VERSION 5.7 ;
  NOWIREEXTENSIONATPIN ON ;
  DIVIDERCHAR "/" ;
  BUSBITCHARS "[]" ;
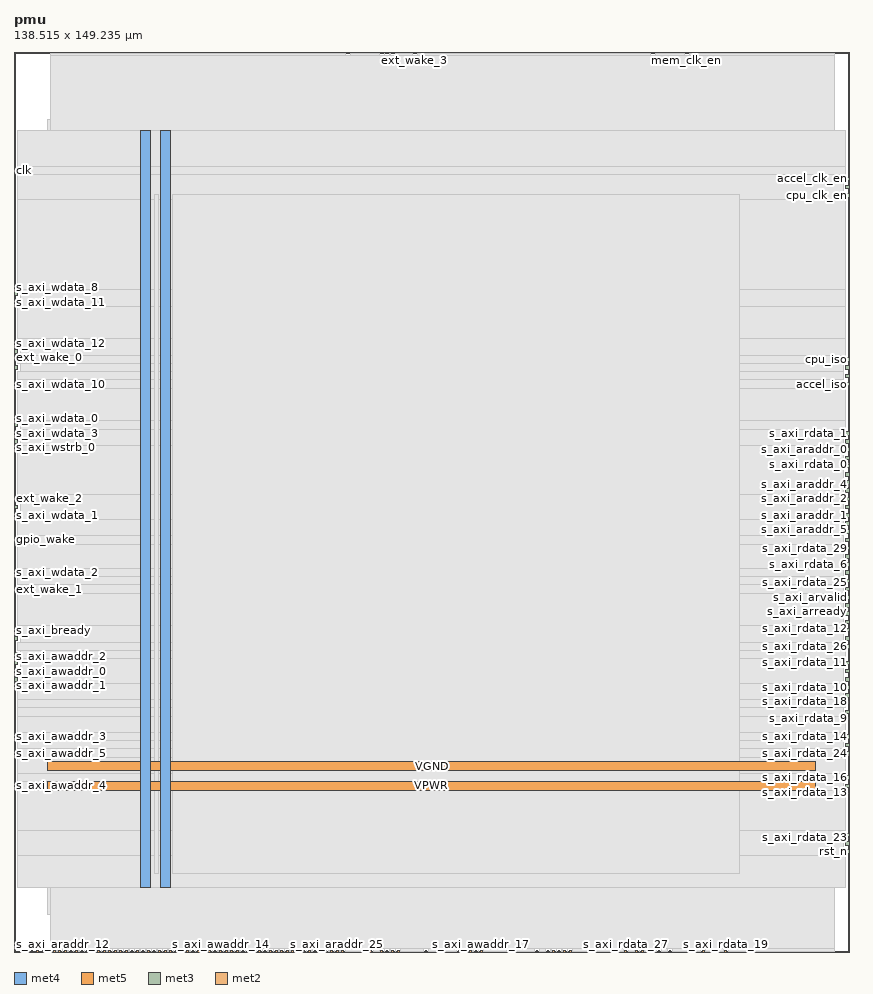
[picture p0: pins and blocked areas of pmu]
MACRO pmu
  CLASS BLOCK ;
  FOREIGN pmu ;
  ORIGIN 0.000 0.000 ;
  SIZE 138.515 BY 149.235 ;
  PIN VGND
    DIRECTION INOUT ;
    USE GROUND ;
    PORT
      LAYER met4 ;
        RECT 24.340 10.640 25.940 136.240 ;
    END
    PORT
      LAYER met5 ;
        RECT 5.520 30.030 132.940 31.630 ;
    END
  END VGND
  PIN VPWR
    DIRECTION INOUT ;
    USE POWER ;
    PORT
      LAYER met4 ;
        RECT 21.040 10.640 22.640 136.240 ;
    END
    PORT
      LAYER met5 ;
        RECT 5.520 26.730 132.940 28.330 ;
    END
  END VPWR
  PIN accel_clk_en
    DIRECTION OUTPUT ;
    USE SIGNAL ;
    ANTENNAGATEAREA 0.434700 ;
    ANTENNADIFFAREA 1.137600 ;
    PORT
      LAYER met3 ;
        RECT 137.915 127.880 138.515 128.480 ;
    END
  END accel_clk_en
  PIN accel_iso
    DIRECTION OUTPUT ;
    USE SIGNAL ;
    ANTENNAGATEAREA 0.434700 ;
    ANTENNADIFFAREA 1.137600 ;
    PORT
      LAYER met3 ;
        RECT 137.915 93.880 138.515 94.480 ;
    END
  END accel_iso
  PIN clk
    DIRECTION INPUT ;
    USE SIGNAL ;
    ANTENNAGATEAREA 1.286700 ;
    ANTENNADIFFAREA 0.434700 ;
    PORT
      LAYER met3 ;
        RECT 0.000 129.240 0.600 129.840 ;
    END
  END clk
  PIN cpu_clk_en
    DIRECTION OUTPUT ;
    USE SIGNAL ;
    ANTENNAGATEAREA 0.434700 ;
    ANTENNADIFFAREA 1.137600 ;
    PORT
      LAYER met3 ;
        RECT 137.915 125.160 138.515 125.760 ;
    END
  END cpu_clk_en
  PIN cpu_iso
    DIRECTION OUTPUT ;
    USE SIGNAL ;
    ANTENNAGATEAREA 0.434700 ;
    ANTENNADIFFAREA 1.137600 ;
    PORT
      LAYER met3 ;
        RECT 137.915 97.960 138.515 98.560 ;
    END
  END cpu_iso
  PIN ext_wake_0
    DIRECTION INPUT ;
    USE SIGNAL ;
    ANTENNAGATEAREA 0.647700 ;
    ANTENNADIFFAREA 0.434700 ;
    PORT
      LAYER met3 ;
        RECT 0.000 99.320 0.600 99.920 ;
    END
  END ext_wake_0
  PIN ext_wake_1
    DIRECTION INPUT ;
    USE SIGNAL ;
    ANTENNAGATEAREA 0.647700 ;
    ANTENNADIFFAREA 0.434700 ;
    PORT
      LAYER met3 ;
        RECT 0.000 59.880 0.600 60.480 ;
    END
  END ext_wake_1
  PIN ext_wake_2
    DIRECTION INPUT ;
    USE SIGNAL ;
    ANTENNAGATEAREA 0.647700 ;
    ANTENNADIFFAREA 0.434700 ;
    PORT
      LAYER met3 ;
        RECT 0.000 74.840 0.600 75.440 ;
    END
  END ext_wake_2
  PIN ext_wake_3
    DIRECTION INPUT ;
    USE SIGNAL ;
    ANTENNAGATEAREA 0.647700 ;
    ANTENNADIFFAREA 0.434700 ;
    PORT
      LAYER met2 ;
        RECT 66.330 148.955 66.610 149.235 ;
    END
  END ext_wake_3
  PIN gpio_wake
    DIRECTION INPUT ;
    USE SIGNAL ;
    ANTENNAGATEAREA 0.647700 ;
    ANTENNADIFFAREA 0.434700 ;
    PORT
      LAYER met3 ;
        RECT 0.000 68.040 0.600 68.640 ;
    END
  END gpio_wake
  PIN mem_clk_en
    DIRECTION OUTPUT ;
    USE SIGNAL ;
    ANTENNAGATEAREA 0.434700 ;
    ANTENNADIFFAREA 1.137600 ;
    PORT
      LAYER met2 ;
        RECT 111.410 148.955 111.690 149.235 ;
    END
  END mem_clk_en
  PIN periph_clk_en
    DIRECTION OUTPUT ;
    USE SIGNAL ;
    ANTENNAGATEAREA 0.434700 ;
    ANTENNADIFFAREA 1.137600 ;
    PORT
      LAYER met3 ;
        RECT 137.915 126.520 138.515 127.120 ;
    END
  END periph_clk_en
  PIN periph_iso
    DIRECTION OUTPUT ;
    USE SIGNAL ;
    ANTENNAGATEAREA 0.434700 ;
    ANTENNADIFFAREA 1.137600 ;
    PORT
      LAYER met3 ;
        RECT 137.915 96.600 138.515 97.200 ;
    END
  END periph_iso
  PIN rst_n
    DIRECTION INPUT ;
    USE SIGNAL ;
    ANTENNAGATEAREA 0.647700 ;
    ANTENNADIFFAREA 0.434700 ;
    PORT
      LAYER met3 ;
        RECT 137.915 16.360 138.515 16.960 ;
    END
  END rst_n
  PIN s_axi_araddr_0
    DIRECTION INPUT ;
    USE SIGNAL ;
    ANTENNAGATEAREA 0.647700 ;
    ANTENNADIFFAREA 0.434700 ;
    PORT
      LAYER met3 ;
        RECT 137.915 83.000 138.515 83.600 ;
    END
  END s_axi_araddr_0
  PIN s_axi_araddr_1
    DIRECTION INPUT ;
    USE SIGNAL ;
    ANTENNAGATEAREA 0.647700 ;
    ANTENNADIFFAREA 0.434700 ;
    PORT
      LAYER met3 ;
        RECT 137.915 72.120 138.515 72.720 ;
    END
  END s_axi_araddr_1
  PIN s_axi_araddr_10
    DIRECTION INPUT ;
    USE SIGNAL ;
    PORT
      LAYER met2 ;
        RECT 3.770 0.000 4.050 0.280 ;
    END
  END s_axi_araddr_10
  PIN s_axi_araddr_11
    DIRECTION INPUT ;
    USE SIGNAL ;
    PORT
      LAYER met2 ;
        RECT 2.850 0.000 3.130 0.280 ;
    END
  END s_axi_araddr_11
  PIN s_axi_araddr_12
    DIRECTION INPUT ;
    USE SIGNAL ;
    PORT
      LAYER met2 ;
        RECT 5.610 0.000 5.890 0.280 ;
    END
  END s_axi_araddr_12
  PIN s_axi_araddr_13
    DIRECTION INPUT ;
    USE SIGNAL ;
    PORT
      LAYER met2 ;
        RECT 4.690 0.000 4.970 0.280 ;
    END
  END s_axi_araddr_13
  PIN s_axi_araddr_14
    DIRECTION INPUT ;
    USE SIGNAL ;
    PORT
      LAYER met2 ;
        RECT 7.450 0.000 7.730 0.280 ;
    END
  END s_axi_araddr_14
  PIN s_axi_araddr_15
    DIRECTION INPUT ;
    USE SIGNAL ;
    PORT
      LAYER met2 ;
        RECT 6.530 0.000 6.810 0.280 ;
    END
  END s_axi_araddr_15
  PIN s_axi_araddr_16
    DIRECTION INPUT ;
    USE SIGNAL ;
    PORT
      LAYER met2 ;
        RECT 9.290 0.000 9.570 0.280 ;
    END
  END s_axi_araddr_16
  PIN s_axi_araddr_17
    DIRECTION INPUT ;
    USE SIGNAL ;
    PORT
      LAYER met2 ;
        RECT 8.370 0.000 8.650 0.280 ;
    END
  END s_axi_araddr_17
  PIN s_axi_araddr_18
    DIRECTION INPUT ;
    USE SIGNAL ;
    PORT
      LAYER met2 ;
        RECT 52.530 0.000 52.810 0.280 ;
    END
  END s_axi_araddr_18
  PIN s_axi_araddr_19
    DIRECTION INPUT ;
    USE SIGNAL ;
    PORT
      LAYER met2 ;
        RECT 10.210 0.000 10.490 0.280 ;
    END
  END s_axi_araddr_19
  PIN s_axi_araddr_2
    DIRECTION INPUT ;
    USE SIGNAL ;
    ANTENNAGATEAREA 0.647700 ;
    ANTENNADIFFAREA 0.434700 ;
    PORT
      LAYER met3 ;
        RECT 137.915 74.840 138.515 75.440 ;
    END
  END s_axi_araddr_2
  PIN s_axi_araddr_20
    DIRECTION INPUT ;
    USE SIGNAL ;
    PORT
      LAYER met2 ;
        RECT 11.130 0.000 11.410 0.280 ;
    END
  END s_axi_araddr_20
  PIN s_axi_araddr_21
    DIRECTION INPUT ;
    USE SIGNAL ;
    PORT
      LAYER met2 ;
        RECT 12.050 0.000 12.330 0.280 ;
    END
  END s_axi_araddr_21
  PIN s_axi_araddr_22
    DIRECTION INPUT ;
    USE SIGNAL ;
    PORT
      LAYER met2 ;
        RECT 12.970 0.000 13.250 0.280 ;
    END
  END s_axi_araddr_22
  PIN s_axi_araddr_23
    DIRECTION INPUT ;
    USE SIGNAL ;
    PORT
      LAYER met2 ;
        RECT 13.890 0.000 14.170 0.280 ;
    END
  END s_axi_araddr_23
  PIN s_axi_araddr_24
    DIRECTION INPUT ;
    USE SIGNAL ;
    PORT
      LAYER met2 ;
        RECT 14.810 0.000 15.090 0.280 ;
    END
  END s_axi_araddr_24
  PIN s_axi_araddr_25
    DIRECTION INPUT ;
    USE SIGNAL ;
    PORT
      LAYER met2 ;
        RECT 53.450 0.000 53.730 0.280 ;
    END
  END s_axi_araddr_25
  PIN s_axi_araddr_26
    DIRECTION INPUT ;
    USE SIGNAL ;
    PORT
      LAYER met2 ;
        RECT 16.650 0.000 16.930 0.280 ;
    END
  END s_axi_araddr_26
  PIN s_axi_araddr_27
    DIRECTION INPUT ;
    USE SIGNAL ;
    PORT
      LAYER met2 ;
        RECT 17.570 0.000 17.850 0.280 ;
    END
  END s_axi_araddr_27
  PIN s_axi_araddr_28
    DIRECTION INPUT ;
    USE SIGNAL ;
    PORT
      LAYER met2 ;
        RECT 18.490 0.000 18.770 0.280 ;
    END
  END s_axi_araddr_28
  PIN s_axi_araddr_29
    DIRECTION INPUT ;
    USE SIGNAL ;
    PORT
      LAYER met2 ;
        RECT 20.330 0.000 20.610 0.280 ;
    END
  END s_axi_araddr_29
  PIN s_axi_araddr_3
    DIRECTION INPUT ;
    USE SIGNAL ;
    ANTENNAGATEAREA 0.647700 ;
    ANTENNADIFFAREA 0.434700 ;
    PORT
      LAYER met3 ;
        RECT 137.915 73.480 138.515 74.080 ;
    END
  END s_axi_araddr_3
  PIN s_axi_araddr_30
    DIRECTION INPUT ;
    USE SIGNAL ;
    PORT
      LAYER met2 ;
        RECT 21.250 0.000 21.530 0.280 ;
    END
  END s_axi_araddr_30
  PIN s_axi_araddr_31
    DIRECTION INPUT ;
    USE SIGNAL ;
    PORT
      LAYER met2 ;
        RECT 22.170 0.000 22.450 0.280 ;
    END
  END s_axi_araddr_31
  PIN s_axi_araddr_4
    DIRECTION INPUT ;
    USE SIGNAL ;
    ANTENNAGATEAREA 0.647700 ;
    ANTENNADIFFAREA 0.434700 ;
    PORT
      LAYER met3 ;
        RECT 137.915 76.200 138.515 76.800 ;
    END
  END s_axi_araddr_4
  PIN s_axi_araddr_5
    DIRECTION INPUT ;
    USE SIGNAL ;
    ANTENNAGATEAREA 0.647700 ;
    ANTENNADIFFAREA 0.434700 ;
    PORT
      LAYER met3 ;
        RECT 137.915 70.760 138.515 71.360 ;
    END
  END s_axi_araddr_5
  PIN s_axi_araddr_6
    DIRECTION INPUT ;
    USE SIGNAL ;
    ANTENNAGATEAREA 0.647700 ;
    ANTENNADIFFAREA 0.434700 ;
    PORT
      LAYER met3 ;
        RECT 137.915 77.560 138.515 78.160 ;
    END
  END s_axi_araddr_6
  PIN s_axi_araddr_7
    DIRECTION INPUT ;
    USE SIGNAL ;
    ANTENNAGATEAREA 0.647700 ;
    ANTENNADIFFAREA 0.434700 ;
    PORT
      LAYER met3 ;
        RECT 137.915 69.400 138.515 70.000 ;
    END
  END s_axi_araddr_7
  PIN s_axi_araddr_8
    DIRECTION INPUT ;
    USE SIGNAL ;
    PORT
      LAYER met2 ;
        RECT 23.090 0.000 23.370 0.280 ;
    END
  END s_axi_araddr_8
  PIN s_axi_araddr_9
    DIRECTION INPUT ;
    USE SIGNAL ;
    PORT
      LAYER met2 ;
        RECT 54.370 0.000 54.650 0.280 ;
    END
  END s_axi_araddr_9
  PIN s_axi_arready
    DIRECTION OUTPUT ;
    USE SIGNAL ;
    ANTENNAGATEAREA 0.434700 ;
    ANTENNADIFFAREA 1.137600 ;
    PORT
      LAYER met3 ;
        RECT 137.915 57.160 138.515 57.760 ;
    END
  END s_axi_arready
  PIN s_axi_arvalid
    DIRECTION INPUT ;
    USE SIGNAL ;
    ANTENNAGATEAREA 0.647700 ;
    ANTENNADIFFAREA 0.434700 ;
    PORT
      LAYER met3 ;
        RECT 137.915 58.520 138.515 59.120 ;
    END
  END s_axi_arvalid
  PIN s_axi_awaddr_0
    DIRECTION INPUT ;
    USE SIGNAL ;
    ANTENNAGATEAREA 0.647700 ;
    ANTENNADIFFAREA 0.434700 ;
    PORT
      LAYER met3 ;
        RECT 0.000 46.280 0.600 46.880 ;
    END
  END s_axi_awaddr_0
  PIN s_axi_awaddr_1
    DIRECTION INPUT ;
    USE SIGNAL ;
    ANTENNAGATEAREA 0.647700 ;
    ANTENNADIFFAREA 0.434700 ;
    PORT
      LAYER met3 ;
        RECT 0.000 44.920 0.600 45.520 ;
    END
  END s_axi_awaddr_1
  PIN s_axi_awaddr_10
    DIRECTION INPUT ;
    USE SIGNAL ;
    ANTENNAGATEAREA 0.647700 ;
    ANTENNADIFFAREA 0.434700 ;
    PORT
      LAYER met2 ;
        RECT 48.850 0.000 49.130 0.280 ;
    END
  END s_axi_awaddr_10
  PIN s_axi_awaddr_11
    DIRECTION INPUT ;
    USE SIGNAL ;
    ANTENNAGATEAREA 0.647700 ;
    ANTENNADIFFAREA 0.434700 ;
    PORT
      LAYER met2 ;
        RECT 61.730 0.000 62.010 0.280 ;
    END
  END s_axi_awaddr_11
  PIN s_axi_awaddr_12
    DIRECTION INPUT ;
    USE SIGNAL ;
    ANTENNAGATEAREA 0.647700 ;
    ANTENNADIFFAREA 0.434700 ;
    PORT
      LAYER met2 ;
        RECT 47.010 0.000 47.290 0.280 ;
    END
  END s_axi_awaddr_12
  PIN s_axi_awaddr_13
    DIRECTION INPUT ;
    USE SIGNAL ;
    ANTENNAGATEAREA 0.647700 ;
    ANTENNADIFFAREA 0.434700 ;
    PORT
      LAYER met2 ;
        RECT 63.570 0.000 63.850 0.280 ;
    END
  END s_axi_awaddr_13
  PIN s_axi_awaddr_14
    DIRECTION INPUT ;
    USE SIGNAL ;
    ANTENNAGATEAREA 0.647700 ;
    ANTENNADIFFAREA 0.434700 ;
    PORT
      LAYER met2 ;
        RECT 34.130 0.000 34.410 0.280 ;
    END
  END s_axi_awaddr_14
  PIN s_axi_awaddr_15
    DIRECTION INPUT ;
    USE SIGNAL ;
    ANTENNAGATEAREA 0.647700 ;
    ANTENNADIFFAREA 0.434700 ;
    PORT
      LAYER met2 ;
        RECT 58.970 0.000 59.250 0.280 ;
    END
  END s_axi_awaddr_15
  PIN s_axi_awaddr_16
    DIRECTION INPUT ;
    USE SIGNAL ;
    ANTENNAGATEAREA 0.647700 ;
    ANTENNADIFFAREA 0.434700 ;
    PORT
      LAYER met2 ;
        RECT 31.370 0.000 31.650 0.280 ;
    END
  END s_axi_awaddr_16
  PIN s_axi_awaddr_17
    DIRECTION INPUT ;
    USE SIGNAL ;
    ANTENNAGATEAREA 0.647700 ;
    ANTENNADIFFAREA 0.434700 ;
    PORT
      LAYER met2 ;
        RECT 77.370 0.000 77.650 0.280 ;
    END
  END s_axi_awaddr_17
  PIN s_axi_awaddr_18
    DIRECTION INPUT ;
    USE SIGNAL ;
    ANTENNAGATEAREA 0.647700 ;
    ANTENNADIFFAREA 0.434700 ;
    PORT
      LAYER met2 ;
        RECT 28.610 0.000 28.890 0.280 ;
    END
  END s_axi_awaddr_18
  PIN s_axi_awaddr_19
    DIRECTION INPUT ;
    USE SIGNAL ;
    ANTENNAGATEAREA 0.647700 ;
    ANTENNADIFFAREA 0.434700 ;
    PORT
      LAYER met2 ;
        RECT 58.050 0.000 58.330 0.280 ;
    END
  END s_axi_awaddr_19
  PIN s_axi_awaddr_2
    DIRECTION INPUT ;
    USE SIGNAL ;
    ANTENNAGATEAREA 0.647700 ;
    ANTENNADIFFAREA 0.434700 ;
    PORT
      LAYER met3 ;
        RECT 0.000 47.640 0.600 48.240 ;
    END
  END s_axi_awaddr_2
  PIN s_axi_awaddr_20
    DIRECTION INPUT ;
    USE SIGNAL ;
    ANTENNAGATEAREA 0.647700 ;
    ANTENNADIFFAREA 0.434700 ;
    PORT
      LAYER met2 ;
        RECT 62.650 0.000 62.930 0.280 ;
    END
  END s_axi_awaddr_20
  PIN s_axi_awaddr_21
    DIRECTION INPUT ;
    USE SIGNAL ;
    ANTENNAGATEAREA 0.647700 ;
    ANTENNADIFFAREA 0.434700 ;
    PORT
      LAYER met2 ;
        RECT 44.250 0.000 44.530 0.280 ;
    END
  END s_axi_awaddr_21
  PIN s_axi_awaddr_22
    DIRECTION INPUT ;
    USE SIGNAL ;
    ANTENNAGATEAREA 0.647700 ;
    ANTENNADIFFAREA 0.434700 ;
    PORT
      LAYER met2 ;
        RECT 39.650 0.000 39.930 0.280 ;
    END
  END s_axi_awaddr_22
  PIN s_axi_awaddr_23
    DIRECTION INPUT ;
    USE SIGNAL ;
    ANTENNAGATEAREA 0.647700 ;
    ANTENNADIFFAREA 0.434700 ;
    PORT
      LAYER met2 ;
        RECT 29.530 0.000 29.810 0.280 ;
    END
  END s_axi_awaddr_23
  PIN s_axi_awaddr_24
    DIRECTION INPUT ;
    USE SIGNAL ;
    ANTENNAGATEAREA 0.647700 ;
    ANTENNADIFFAREA 0.434700 ;
    PORT
      LAYER met2 ;
        RECT 81.970 0.000 82.250 0.280 ;
    END
  END s_axi_awaddr_24
  PIN s_axi_awaddr_25
    DIRECTION INPUT ;
    USE SIGNAL ;
    ANTENNAGATEAREA 0.647700 ;
    ANTENNADIFFAREA 0.434700 ;
    PORT
      LAYER met2 ;
        RECT 88.410 0.000 88.690 0.280 ;
    END
  END s_axi_awaddr_25
  PIN s_axi_awaddr_26
    DIRECTION INPUT ;
    USE SIGNAL ;
    ANTENNAGATEAREA 0.647700 ;
    ANTENNADIFFAREA 0.434700 ;
    PORT
      LAYER met2 ;
        RECT 74.610 0.000 74.890 0.280 ;
    END
  END s_axi_awaddr_26
  PIN s_axi_awaddr_27
    DIRECTION INPUT ;
    USE SIGNAL ;
    ANTENNAGATEAREA 0.647700 ;
    ANTENNADIFFAREA 0.434700 ;
    PORT
      LAYER met2 ;
        RECT 92.090 0.000 92.370 0.280 ;
    END
  END s_axi_awaddr_27
  PIN s_axi_awaddr_28
    DIRECTION INPUT ;
    USE SIGNAL ;
    ANTENNAGATEAREA 0.647700 ;
    ANTENNADIFFAREA 0.434700 ;
    PORT
      LAYER met2 ;
        RECT 90.250 0.000 90.530 0.280 ;
    END
  END s_axi_awaddr_28
  PIN s_axi_awaddr_29
    DIRECTION INPUT ;
    USE SIGNAL ;
    ANTENNAGATEAREA 0.647700 ;
    ANTENNADIFFAREA 0.434700 ;
    PORT
      LAYER met2 ;
        RECT 76.450 0.000 76.730 0.280 ;
    END
  END s_axi_awaddr_29
  PIN s_axi_awaddr_3
    DIRECTION INPUT ;
    USE SIGNAL ;
    ANTENNAGATEAREA 0.647700 ;
    ANTENNADIFFAREA 0.434700 ;
    PORT
      LAYER met3 ;
        RECT 0.000 35.400 0.600 36.000 ;
    END
  END s_axi_awaddr_3
  PIN s_axi_awaddr_30
    DIRECTION INPUT ;
    USE SIGNAL ;
    ANTENNAGATEAREA 0.647700 ;
    ANTENNADIFFAREA 0.434700 ;
    PORT
      LAYER met2 ;
        RECT 91.170 0.000 91.450 0.280 ;
    END
  END s_axi_awaddr_30
  PIN s_axi_awaddr_31
    DIRECTION INPUT ;
    USE SIGNAL ;
    ANTENNAGATEAREA 0.647700 ;
    ANTENNADIFFAREA 0.434700 ;
    PORT
      LAYER met2 ;
        RECT 89.330 0.000 89.610 0.280 ;
    END
  END s_axi_awaddr_31
  PIN s_axi_awaddr_4
    DIRECTION INPUT ;
    USE SIGNAL ;
    ANTENNAGATEAREA 0.647700 ;
    ANTENNADIFFAREA 0.434700 ;
    PORT
      LAYER met3 ;
        RECT 0.000 27.240 0.600 27.840 ;
    END
  END s_axi_awaddr_4
  PIN s_axi_awaddr_5
    DIRECTION INPUT ;
    USE SIGNAL ;
    ANTENNAGATEAREA 0.647700 ;
    ANTENNADIFFAREA 0.434700 ;
    PORT
      LAYER met3 ;
        RECT 0.000 32.680 0.600 33.280 ;
    END
  END s_axi_awaddr_5
  PIN s_axi_awaddr_6
    DIRECTION INPUT ;
    USE SIGNAL ;
    ANTENNAGATEAREA 0.647700 ;
    ANTENNADIFFAREA 0.434700 ;
    PORT
      LAYER met2 ;
        RECT 15.730 0.000 16.010 0.280 ;
    END
  END s_axi_awaddr_6
  PIN s_axi_awaddr_7
    DIRECTION INPUT ;
    USE SIGNAL ;
    ANTENNAGATEAREA 0.647700 ;
    ANTENNADIFFAREA 0.434700 ;
    PORT
      LAYER met2 ;
        RECT 19.410 0.000 19.690 0.280 ;
    END
  END s_axi_awaddr_7
  PIN s_axi_awaddr_8
    DIRECTION INPUT ;
    USE SIGNAL ;
    ANTENNAGATEAREA 0.647700 ;
    ANTENNADIFFAREA 0.434700 ;
    PORT
      LAYER met2 ;
        RECT 45.170 0.000 45.450 0.280 ;
    END
  END s_axi_awaddr_8
  PIN s_axi_awaddr_9
    DIRECTION INPUT ;
    USE SIGNAL ;
    ANTENNAGATEAREA 0.647700 ;
    ANTENNADIFFAREA 0.434700 ;
    PORT
      LAYER met2 ;
        RECT 73.690 0.000 73.970 0.280 ;
    END
  END s_axi_awaddr_9
  PIN s_axi_awready
    DIRECTION OUTPUT ;
    USE SIGNAL ;
    PORT
      LAYER met2 ;
        RECT 24.010 0.000 24.290 0.280 ;
    END
  END s_axi_awready
  PIN s_axi_awvalid
    DIRECTION INPUT ;
    USE SIGNAL ;
    ANTENNAGATEAREA 0.647700 ;
    ANTENNADIFFAREA 0.434700 ;
    PORT
      LAYER met2 ;
        RECT 47.930 0.000 48.210 0.280 ;
    END
  END s_axi_awvalid
  PIN s_axi_bready
    DIRECTION INPUT ;
    USE SIGNAL ;
    ANTENNAGATEAREA 0.647700 ;
    ANTENNADIFFAREA 0.434700 ;
    PORT
      LAYER met3 ;
        RECT 0.000 53.080 0.600 53.680 ;
    END
  END s_axi_bready
  PIN s_axi_bresp_0
    DIRECTION OUTPUT ;
    USE SIGNAL ;
    PORT
      LAYER met2 ;
        RECT 24.930 0.000 25.210 0.280 ;
    END
  END s_axi_bresp_0
  PIN s_axi_bresp_1
    DIRECTION OUTPUT ;
    USE SIGNAL ;
    PORT
      LAYER met2 ;
        RECT 25.850 0.000 26.130 0.280 ;
    END
  END s_axi_bresp_1
  PIN s_axi_bvalid
    DIRECTION OUTPUT ;
    USE SIGNAL ;
    ANTENNAGATEAREA 0.434700 ;
    ANTENNADIFFAREA 1.137600 ;
    PORT
      LAYER met3 ;
        RECT 0.000 51.720 0.600 52.320 ;
    END
  END s_axi_bvalid
  PIN s_axi_rdata_0
    DIRECTION OUTPUT ;
    USE SIGNAL ;
    ANTENNAGATEAREA 0.434700 ;
    ANTENNADIFFAREA 1.137600 ;
    PORT
      LAYER met3 ;
        RECT 137.915 81.640 138.515 82.240 ;
    END
  END s_axi_rdata_0
  PIN s_axi_rdata_1
    DIRECTION OUTPUT ;
    USE SIGNAL ;
    ANTENNAGATEAREA 0.434700 ;
    ANTENNADIFFAREA 1.137600 ;
    PORT
      LAYER met3 ;
        RECT 137.915 85.720 138.515 86.320 ;
    END
  END s_axi_rdata_1
  PIN s_axi_rdata_10
    DIRECTION OUTPUT ;
    USE SIGNAL ;
    ANTENNAGATEAREA 0.434700 ;
    ANTENNADIFFAREA 1.137600 ;
    PORT
      LAYER met3 ;
        RECT 137.915 43.560 138.515 44.160 ;
    END
  END s_axi_rdata_10
  PIN s_axi_rdata_11
    DIRECTION OUTPUT ;
    USE SIGNAL ;
    ANTENNAGATEAREA 0.434700 ;
    ANTENNADIFFAREA 1.137600 ;
    PORT
      LAYER met3 ;
        RECT 137.915 47.640 138.515 48.240 ;
    END
  END s_axi_rdata_11
  PIN s_axi_rdata_12
    DIRECTION OUTPUT ;
    USE SIGNAL ;
    ANTENNAGATEAREA 0.434700 ;
    ANTENNADIFFAREA 1.137600 ;
    PORT
      LAYER met3 ;
        RECT 137.915 54.440 138.515 55.040 ;
    END
  END s_axi_rdata_12
  PIN s_axi_rdata_13
    DIRECTION OUTPUT ;
    USE SIGNAL ;
    ANTENNAGATEAREA 0.434700 ;
    ANTENNADIFFAREA 1.137600 ;
    PORT
      LAYER met3 ;
        RECT 137.915 27.240 138.515 27.840 ;
    END
  END s_axi_rdata_13
  PIN s_axi_rdata_14
    DIRECTION OUTPUT ;
    USE SIGNAL ;
    ANTENNAGATEAREA 0.434700 ;
    ANTENNADIFFAREA 1.137600 ;
    PORT
      LAYER met3 ;
        RECT 137.915 35.400 138.515 36.000 ;
    END
  END s_axi_rdata_14
  PIN s_axi_rdata_15
    DIRECTION OUTPUT ;
    USE SIGNAL ;
    ANTENNAGATEAREA 0.434700 ;
    ANTENNADIFFAREA 1.137600 ;
    PORT
      LAYER met2 ;
        RECT 108.650 0.000 108.930 0.280 ;
    END
  END s_axi_rdata_15
  PIN s_axi_rdata_16
    DIRECTION OUTPUT ;
    USE SIGNAL ;
    ANTENNAGATEAREA 0.434700 ;
    ANTENNADIFFAREA 1.137600 ;
    PORT
      LAYER met3 ;
        RECT 137.915 28.600 138.515 29.200 ;
    END
  END s_axi_rdata_16
  PIN s_axi_rdata_17
    DIRECTION OUTPUT ;
    USE SIGNAL ;
    ANTENNAGATEAREA 0.434700 ;
    ANTENNADIFFAREA 1.137600 ;
    PORT
      LAYER met3 ;
        RECT 137.915 44.920 138.515 45.520 ;
    END
  END s_axi_rdata_17
  PIN s_axi_rdata_18
    DIRECTION OUTPUT ;
    USE SIGNAL ;
    ANTENNAGATEAREA 0.434700 ;
    ANTENNADIFFAREA 1.137600 ;
    PORT
      LAYER met3 ;
        RECT 137.915 42.200 138.515 42.800 ;
    END
  END s_axi_rdata_18
  PIN s_axi_rdata_19
    DIRECTION OUTPUT ;
    USE SIGNAL ;
    ANTENNAGATEAREA 0.434700 ;
    ANTENNADIFFAREA 1.137600 ;
    PORT
      LAYER met2 ;
        RECT 117.850 0.000 118.130 0.280 ;
    END
  END s_axi_rdata_19
  PIN s_axi_rdata_2
    DIRECTION OUTPUT ;
    USE SIGNAL ;
    ANTENNAGATEAREA 0.434700 ;
    ANTENNADIFFAREA 1.137600 ;
    PORT
      LAYER met2 ;
        RECT 103.130 0.000 103.410 0.280 ;
    END
  END s_axi_rdata_2
  PIN s_axi_rdata_20
    DIRECTION OUTPUT ;
    USE SIGNAL ;
    ANTENNAGATEAREA 0.434700 ;
    ANTENNADIFFAREA 1.137600 ;
    PORT
      LAYER met3 ;
        RECT 137.915 55.800 138.515 56.400 ;
    END
  END s_axi_rdata_20
  PIN s_axi_rdata_21
    DIRECTION OUTPUT ;
    USE SIGNAL ;
    ANTENNAGATEAREA 0.434700 ;
    ANTENNADIFFAREA 1.137600 ;
    PORT
      LAYER met3 ;
        RECT 137.915 53.080 138.515 53.680 ;
    END
  END s_axi_rdata_21
  PIN s_axi_rdata_22
    DIRECTION OUTPUT ;
    USE SIGNAL ;
    ANTENNAGATEAREA 0.434700 ;
    ANTENNADIFFAREA 1.137600 ;
    PORT
      LAYER met3 ;
        RECT 137.915 61.240 138.515 61.840 ;
    END
  END s_axi_rdata_22
  PIN s_axi_rdata_23
    DIRECTION OUTPUT ;
    USE SIGNAL ;
    ANTENNAGATEAREA 0.434700 ;
    ANTENNADIFFAREA 1.137600 ;
    PORT
      LAYER met3 ;
        RECT 137.915 17.720 138.515 18.320 ;
    END
  END s_axi_rdata_23
  PIN s_axi_rdata_24
    DIRECTION OUTPUT ;
    USE SIGNAL ;
    ANTENNAGATEAREA 0.434700 ;
    ANTENNADIFFAREA 1.137600 ;
    PORT
      LAYER met3 ;
        RECT 137.915 32.680 138.515 33.280 ;
    END
  END s_axi_rdata_24
  PIN s_axi_rdata_25
    DIRECTION OUTPUT ;
    USE SIGNAL ;
    ANTENNAGATEAREA 0.434700 ;
    ANTENNADIFFAREA 1.137600 ;
    PORT
      LAYER met3 ;
        RECT 137.915 59.880 138.515 60.480 ;
    END
  END s_axi_rdata_25
  PIN s_axi_rdata_26
    DIRECTION OUTPUT ;
    USE SIGNAL ;
    ANTENNAGATEAREA 0.434700 ;
    ANTENNADIFFAREA 1.137600 ;
    PORT
      LAYER met3 ;
        RECT 137.915 50.360 138.515 50.960 ;
    END
  END s_axi_rdata_26
  PIN s_axi_rdata_27
    DIRECTION OUTPUT ;
    USE SIGNAL ;
    ANTENNAGATEAREA 0.434700 ;
    ANTENNADIFFAREA 1.137600 ;
    PORT
      LAYER met2 ;
        RECT 101.290 0.000 101.570 0.280 ;
    END
  END s_axi_rdata_27
  PIN s_axi_rdata_28
    DIRECTION OUTPUT ;
    USE SIGNAL ;
    ANTENNAGATEAREA 0.434700 ;
    ANTENNADIFFAREA 1.137600 ;
    PORT
      LAYER met3 ;
        RECT 137.915 19.080 138.515 19.680 ;
    END
  END s_axi_rdata_28
  PIN s_axi_rdata_29
    DIRECTION OUTPUT ;
    USE SIGNAL ;
    ANTENNAGATEAREA 0.434700 ;
    ANTENNADIFFAREA 1.137600 ;
    PORT
      LAYER met3 ;
        RECT 137.915 66.680 138.515 67.280 ;
    END
  END s_axi_rdata_29
  PIN s_axi_rdata_3
    DIRECTION OUTPUT ;
    USE SIGNAL ;
    ANTENNAGATEAREA 0.434700 ;
    ANTENNADIFFAREA 1.137600 ;
    PORT
      LAYER met2 ;
        RECT 106.810 0.000 107.090 0.280 ;
    END
  END s_axi_rdata_3
  PIN s_axi_rdata_30
    DIRECTION OUTPUT ;
    USE SIGNAL ;
    ANTENNAGATEAREA 0.434700 ;
    ANTENNADIFFAREA 1.137600 ;
    PORT
      LAYER met2 ;
        RECT 114.170 0.000 114.450 0.280 ;
    END
  END s_axi_rdata_30
  PIN s_axi_rdata_31
    DIRECTION OUTPUT ;
    USE SIGNAL ;
    ANTENNAGATEAREA 0.434700 ;
    ANTENNADIFFAREA 1.137600 ;
    PORT
      LAYER met3 ;
        RECT 137.915 46.280 138.515 46.880 ;
    END
  END s_axi_rdata_31
  PIN s_axi_rdata_4
    DIRECTION OUTPUT ;
    USE SIGNAL ;
    ANTENNAGATEAREA 0.434700 ;
    ANTENNADIFFAREA 1.137600 ;
    PORT
      LAYER met3 ;
        RECT 137.915 84.360 138.515 84.960 ;
    END
  END s_axi_rdata_4
  PIN s_axi_rdata_5
    DIRECTION OUTPUT ;
    USE SIGNAL ;
    ANTENNAGATEAREA 0.434700 ;
    ANTENNADIFFAREA 1.137600 ;
    PORT
      LAYER met3 ;
        RECT 137.915 80.280 138.515 80.880 ;
    END
  END s_axi_rdata_5
  PIN s_axi_rdata_6
    DIRECTION OUTPUT ;
    USE SIGNAL ;
    ANTENNAGATEAREA 0.434700 ;
    ANTENNADIFFAREA 1.137600 ;
    PORT
      LAYER met3 ;
        RECT 137.915 63.960 138.515 64.560 ;
    END
  END s_axi_rdata_6
  PIN s_axi_rdata_7
    DIRECTION OUTPUT ;
    USE SIGNAL ;
    ANTENNAGATEAREA 0.434700 ;
    ANTENNADIFFAREA 1.137600 ;
    PORT
      LAYER met3 ;
        RECT 137.915 34.040 138.515 34.640 ;
    END
  END s_axi_rdata_7
  PIN s_axi_rdata_8
    DIRECTION OUTPUT ;
    USE SIGNAL ;
    ANTENNAGATEAREA 0.434700 ;
    ANTENNADIFFAREA 1.137600 ;
    PORT
      LAYER met3 ;
        RECT 137.915 51.720 138.515 52.320 ;
    END
  END s_axi_rdata_8
  PIN s_axi_rdata_9
    DIRECTION OUTPUT ;
    USE SIGNAL ;
    ANTENNAGATEAREA 0.434700 ;
    ANTENNADIFFAREA 1.137600 ;
    PORT
      LAYER met3 ;
        RECT 137.915 39.480 138.515 40.080 ;
    END
  END s_axi_rdata_9
  PIN s_axi_rready
    DIRECTION INPUT ;
    USE SIGNAL ;
    ANTENNAGATEAREA 0.647700 ;
    ANTENNADIFFAREA 0.434700 ;
    PORT
      LAYER met3 ;
        RECT 137.915 62.600 138.515 63.200 ;
    END
  END s_axi_rready
  PIN s_axi_rresp_0
    DIRECTION OUTPUT ;
    USE SIGNAL ;
    ANTENNAGATEAREA 0.434700 ;
    ANTENNADIFFAREA 1.137600 ;
    PORT
      LAYER met2 ;
        RECT 104.050 0.000 104.330 0.280 ;
    END
  END s_axi_rresp_0
  PIN s_axi_rresp_1
    DIRECTION OUTPUT ;
    USE SIGNAL ;
    ANTENNAGATEAREA 0.434700 ;
    ANTENNADIFFAREA 1.137600 ;
    PORT
      LAYER met3 ;
        RECT 137.915 65.320 138.515 65.920 ;
    END
  END s_axi_rresp_1
  PIN s_axi_rvalid
    DIRECTION OUTPUT ;
    USE SIGNAL ;
    ANTENNAGATEAREA 0.434700 ;
    ANTENNADIFFAREA 1.137600 ;
    PORT
      LAYER met3 ;
        RECT 137.915 68.040 138.515 68.640 ;
    END
  END s_axi_rvalid
  PIN s_axi_wdata_0
    DIRECTION INPUT ;
    USE SIGNAL ;
    ANTENNAGATEAREA 0.647700 ;
    ANTENNADIFFAREA 0.434700 ;
    PORT
      LAYER met3 ;
        RECT 0.000 87.080 0.600 87.680 ;
    END
  END s_axi_wdata_0
  PIN s_axi_wdata_1
    DIRECTION INPUT ;
    USE SIGNAL ;
    ANTENNAGATEAREA 0.647700 ;
    ANTENNADIFFAREA 0.434700 ;
    PORT
      LAYER met3 ;
        RECT 0.000 72.120 0.600 72.720 ;
    END
  END s_axi_wdata_1
  PIN s_axi_wdata_10
    DIRECTION INPUT ;
    USE SIGNAL ;
    ANTENNAGATEAREA 0.647700 ;
    ANTENNADIFFAREA 0.434700 ;
    PORT
      LAYER met3 ;
        RECT 0.000 93.880 0.600 94.480 ;
    END
  END s_axi_wdata_10
  PIN s_axi_wdata_11
    DIRECTION INPUT ;
    USE SIGNAL ;
    ANTENNAGATEAREA 0.647700 ;
    ANTENNADIFFAREA 0.434700 ;
    PORT
      LAYER met3 ;
        RECT 0.000 107.480 0.600 108.080 ;
    END
  END s_axi_wdata_11
  PIN s_axi_wdata_12
    DIRECTION INPUT ;
    USE SIGNAL ;
    ANTENNAGATEAREA 0.647700 ;
    ANTENNADIFFAREA 0.434700 ;
    PORT
      LAYER met3 ;
        RECT 0.000 100.680 0.600 101.280 ;
    END
  END s_axi_wdata_12
  PIN s_axi_wdata_13
    DIRECTION INPUT ;
    USE SIGNAL ;
    ANTENNAGATEAREA 0.647700 ;
    ANTENNADIFFAREA 0.434700 ;
    PORT
      LAYER met2 ;
        RECT 61.730 148.955 62.010 149.235 ;
    END
  END s_axi_wdata_13
  PIN s_axi_wdata_14
    DIRECTION INPUT ;
    USE SIGNAL ;
    ANTENNAGATEAREA 0.647700 ;
    ANTENNADIFFAREA 0.434700 ;
    PORT
      LAYER met2 ;
        RECT 55.290 148.955 55.570 149.235 ;
    END
  END s_axi_wdata_14
  PIN s_axi_wdata_15
    DIRECTION INPUT ;
    USE SIGNAL ;
    ANTENNAGATEAREA 0.647700 ;
    ANTENNADIFFAREA 0.434700 ;
    PORT
      LAYER met2 ;
        RECT 62.650 148.955 62.930 149.235 ;
    END
  END s_axi_wdata_15
  PIN s_axi_wdata_16
    DIRECTION INPUT ;
    USE SIGNAL ;
    PORT
      LAYER met2 ;
        RECT 26.770 0.000 27.050 0.280 ;
    END
  END s_axi_wdata_16
  PIN s_axi_wdata_17
    DIRECTION INPUT ;
    USE SIGNAL ;
    PORT
      LAYER met2 ;
        RECT 27.690 0.000 27.970 0.280 ;
    END
  END s_axi_wdata_17
  PIN s_axi_wdata_18
    DIRECTION INPUT ;
    USE SIGNAL ;
    PORT
      LAYER met2 ;
        RECT 1.930 0.000 2.210 0.280 ;
    END
  END s_axi_wdata_18
  PIN s_axi_wdata_19
    DIRECTION INPUT ;
    USE SIGNAL ;
    PORT
      LAYER met2 ;
        RECT 30.450 0.000 30.730 0.280 ;
    END
  END s_axi_wdata_19
  PIN s_axi_wdata_2
    DIRECTION INPUT ;
    USE SIGNAL ;
    ANTENNAGATEAREA 0.647700 ;
    ANTENNADIFFAREA 0.434700 ;
    PORT
      LAYER met3 ;
        RECT 0.000 62.600 0.600 63.200 ;
    END
  END s_axi_wdata_2
  PIN s_axi_wdata_20
    DIRECTION INPUT ;
    USE SIGNAL ;
    PORT
      LAYER met2 ;
        RECT 32.290 0.000 32.570 0.280 ;
    END
  END s_axi_wdata_20
  PIN s_axi_wdata_21
    DIRECTION INPUT ;
    USE SIGNAL ;
    PORT
      LAYER met2 ;
        RECT 33.210 0.000 33.490 0.280 ;
    END
  END s_axi_wdata_21
  PIN s_axi_wdata_22
    DIRECTION INPUT ;
    USE SIGNAL ;
    PORT
      LAYER met2 ;
        RECT 35.050 0.000 35.330 0.280 ;
    END
  END s_axi_wdata_22
  PIN s_axi_wdata_23
    DIRECTION INPUT ;
    USE SIGNAL ;
    PORT
      LAYER met2 ;
        RECT 35.970 0.000 36.250 0.280 ;
    END
  END s_axi_wdata_23
  PIN s_axi_wdata_24
    DIRECTION INPUT ;
    USE SIGNAL ;
    PORT
      LAYER met2 ;
        RECT 36.890 0.000 37.170 0.280 ;
    END
  END s_axi_wdata_24
  PIN s_axi_wdata_25
    DIRECTION INPUT ;
    USE SIGNAL ;
    PORT
      LAYER met2 ;
        RECT 37.810 0.000 38.090 0.280 ;
    END
  END s_axi_wdata_25
  PIN s_axi_wdata_26
    DIRECTION INPUT ;
    USE SIGNAL ;
    PORT
      LAYER met2 ;
        RECT 38.730 0.000 39.010 0.280 ;
    END
  END s_axi_wdata_26
  PIN s_axi_wdata_27
    DIRECTION INPUT ;
    USE SIGNAL ;
    PORT
      LAYER met2 ;
        RECT 40.570 0.000 40.850 0.280 ;
    END
  END s_axi_wdata_27
  PIN s_axi_wdata_28
    DIRECTION INPUT ;
    USE SIGNAL ;
    PORT
      LAYER met2 ;
        RECT 41.490 0.000 41.770 0.280 ;
    END
  END s_axi_wdata_28
  PIN s_axi_wdata_29
    DIRECTION INPUT ;
    USE SIGNAL ;
    PORT
      LAYER met2 ;
        RECT 42.410 0.000 42.690 0.280 ;
    END
  END s_axi_wdata_29
  PIN s_axi_wdata_3
    DIRECTION INPUT ;
    USE SIGNAL ;
    ANTENNAGATEAREA 0.647700 ;
    ANTENNADIFFAREA 0.434700 ;
    PORT
      LAYER met3 ;
        RECT 0.000 85.720 0.600 86.320 ;
    END
  END s_axi_wdata_3
  PIN s_axi_wdata_30
    DIRECTION INPUT ;
    USE SIGNAL ;
    PORT
      LAYER met2 ;
        RECT 43.330 0.000 43.610 0.280 ;
    END
  END s_axi_wdata_30
  PIN s_axi_wdata_31
    DIRECTION INPUT ;
    USE SIGNAL ;
    PORT
      LAYER met2 ;
        RECT 46.090 0.000 46.370 0.280 ;
    END
  END s_axi_wdata_31
  PIN s_axi_wdata_4
    DIRECTION INPUT ;
    USE SIGNAL ;
    ANTENNAGATEAREA 0.647700 ;
    ANTENNADIFFAREA 0.434700 ;
    PORT
      LAYER met3 ;
        RECT 137.915 78.920 138.515 79.520 ;
    END
  END s_axi_wdata_4
  PIN s_axi_wdata_5
    DIRECTION INPUT ;
    USE SIGNAL ;
    ANTENNAGATEAREA 0.647700 ;
    ANTENNADIFFAREA 0.434700 ;
    PORT
      LAYER met3 ;
        RECT 0.000 73.480 0.600 74.080 ;
    END
  END s_axi_wdata_5
  PIN s_axi_wdata_6
    DIRECTION INPUT ;
    USE SIGNAL ;
    ANTENNAGATEAREA 0.647700 ;
    ANTENNADIFFAREA 0.434700 ;
    PORT
      LAYER met2 ;
        RECT 60.810 0.000 61.090 0.280 ;
    END
  END s_axi_wdata_6
  PIN s_axi_wdata_7
    DIRECTION INPUT ;
    USE SIGNAL ;
    ANTENNAGATEAREA 0.647700 ;
    ANTENNADIFFAREA 0.434700 ;
    PORT
      LAYER met2 ;
        RECT 75.530 0.000 75.810 0.280 ;
    END
  END s_axi_wdata_7
  PIN s_axi_wdata_8
    DIRECTION INPUT ;
    USE SIGNAL ;
    ANTENNAGATEAREA 0.647700 ;
    ANTENNADIFFAREA 0.434700 ;
    PORT
      LAYER met3 ;
        RECT 0.000 108.840 0.600 109.440 ;
    END
  END s_axi_wdata_8
  PIN s_axi_wdata_9
    DIRECTION INPUT ;
    USE SIGNAL ;
    ANTENNAGATEAREA 0.647700 ;
    ANTENNADIFFAREA 0.434700 ;
    PORT
      LAYER met3 ;
        RECT 0.000 96.600 0.600 97.200 ;
    END
  END s_axi_wdata_9
  PIN s_axi_wready
    DIRECTION OUTPUT ;
    USE SIGNAL ;
    PORT
      LAYER met2 ;
        RECT 49.770 0.000 50.050 0.280 ;
    END
  END s_axi_wready
  PIN s_axi_wstrb_0
    DIRECTION INPUT ;
    USE SIGNAL ;
    ANTENNAGATEAREA 0.647700 ;
    ANTENNADIFFAREA 0.434700 ;
    PORT
      LAYER met3 ;
        RECT 0.000 84.360 0.600 84.960 ;
    END
  END s_axi_wstrb_0
  PIN s_axi_wstrb_1
    DIRECTION INPUT ;
    USE SIGNAL ;
    ANTENNAGATEAREA 0.647700 ;
    ANTENNADIFFAREA 0.434700 ;
    PORT
      LAYER met2 ;
        RECT 60.810 148.955 61.090 149.235 ;
    END
  END s_axi_wstrb_1
  PIN s_axi_wstrb_2
    DIRECTION INPUT ;
    USE SIGNAL ;
    PORT
      LAYER met2 ;
        RECT 50.690 0.000 50.970 0.280 ;
    END
  END s_axi_wstrb_2
  PIN s_axi_wstrb_3
    DIRECTION INPUT ;
    USE SIGNAL ;
    PORT
      LAYER met2 ;
        RECT 51.610 0.000 51.890 0.280 ;
    END
  END s_axi_wstrb_3
  PIN s_axi_wvalid
    DIRECTION INPUT ;
    USE SIGNAL ;
    ANTENNAGATEAREA 0.647700 ;
    ANTENNADIFFAREA 0.434700 ;
    PORT
      LAYER met3 ;
        RECT 0.000 49.000 0.600 49.600 ;
    END
  END s_axi_wvalid
  PIN sram_ret_en
    DIRECTION OUTPUT ;
    USE SIGNAL ;
    ANTENNAGATEAREA 0.434700 ;
    ANTENNADIFFAREA 1.137600 ;
    PORT
      LAYER met3 ;
        RECT 137.915 95.240 138.515 95.840 ;
    END
  END sram_ret_en
  PIN timer_wake
    DIRECTION INPUT ;
    USE SIGNAL ;
    ANTENNAGATEAREA 0.647700 ;
    ANTENNADIFFAREA 0.434700 ;
    PORT
      LAYER met2 ;
        RECT 86.570 0.000 86.850 0.280 ;
    END
  END timer_wake
  PIN uart_wake
    DIRECTION INPUT ;
    USE SIGNAL ;
    ANTENNAGATEAREA 0.647700 ;
    ANTENNADIFFAREA 0.434700 ;
    PORT
      LAYER met2 ;
        RECT 68.170 0.000 68.450 0.280 ;
    END
  END uart_wake
  PIN wake_irq
    DIRECTION OUTPUT ;
    USE SIGNAL ;
    ANTENNAGATEAREA 0.434700 ;
    ANTENNADIFFAREA 0.434700 ;
    PORT
      LAYER met2 ;
        RECT 105.890 148.955 106.170 149.235 ;
    END
  END wake_irq
  OBS
      LAYER nwell ;
        RECT 5.330 10.795 133.130 136.085 ;
      LAYER li1 ;
        RECT 5.520 10.795 132.940 136.085 ;
      LAYER met1 ;
        RECT 5.520 6.160 135.630 138.000 ;
      LAYER met2 ;
        RECT 6.070 148.675 55.010 148.955 ;
        RECT 55.850 148.675 60.530 148.955 ;
        RECT 61.370 148.675 61.450 148.955 ;
        RECT 62.290 148.675 62.370 148.955 ;
        RECT 63.210 148.675 66.050 148.955 ;
        RECT 66.890 148.675 105.610 148.955 ;
        RECT 106.450 148.675 111.130 148.955 ;
        RECT 111.970 148.675 136.070 148.955 ;
        RECT 6.070 0.560 136.070 148.675 ;
        RECT 6.170 0.070 6.250 0.560 ;
        RECT 7.090 0.070 7.170 0.560 ;
        RECT 8.010 0.070 8.090 0.560 ;
        RECT 8.930 0.070 9.010 0.560 ;
        RECT 9.850 0.070 9.930 0.560 ;
        RECT 10.770 0.070 10.850 0.560 ;
        RECT 11.690 0.070 11.770 0.560 ;
        RECT 12.610 0.070 12.690 0.560 ;
        RECT 13.530 0.070 13.610 0.560 ;
        RECT 14.450 0.070 14.530 0.560 ;
        RECT 15.370 0.070 15.450 0.560 ;
        RECT 16.290 0.070 16.370 0.560 ;
        RECT 17.210 0.070 17.290 0.560 ;
        RECT 18.130 0.070 18.210 0.560 ;
        RECT 19.050 0.070 19.130 0.560 ;
        RECT 19.970 0.070 20.050 0.560 ;
        RECT 20.890 0.070 20.970 0.560 ;
        RECT 21.810 0.070 21.890 0.560 ;
        RECT 22.730 0.070 22.810 0.560 ;
        RECT 23.650 0.070 23.730 0.560 ;
        RECT 24.570 0.070 24.650 0.560 ;
        RECT 25.490 0.070 25.570 0.560 ;
        RECT 26.410 0.070 26.490 0.560 ;
        RECT 27.330 0.070 27.410 0.560 ;
        RECT 28.250 0.070 28.330 0.560 ;
        RECT 29.170 0.070 29.250 0.560 ;
        RECT 30.090 0.070 30.170 0.560 ;
        RECT 31.010 0.070 31.090 0.560 ;
        RECT 31.930 0.070 32.010 0.560 ;
        RECT 32.850 0.070 32.930 0.560 ;
        RECT 33.770 0.070 33.850 0.560 ;
        RECT 34.690 0.070 34.770 0.560 ;
        RECT 35.610 0.070 35.690 0.560 ;
        RECT 36.530 0.070 36.610 0.560 ;
        RECT 37.450 0.070 37.530 0.560 ;
        RECT 38.370 0.070 38.450 0.560 ;
        RECT 39.290 0.070 39.370 0.560 ;
        RECT 40.210 0.070 40.290 0.560 ;
        RECT 41.130 0.070 41.210 0.560 ;
        RECT 42.050 0.070 42.130 0.560 ;
        RECT 42.970 0.070 43.050 0.560 ;
        RECT 43.890 0.070 43.970 0.560 ;
        RECT 44.810 0.070 44.890 0.560 ;
        RECT 45.730 0.070 45.810 0.560 ;
        RECT 46.650 0.070 46.730 0.560 ;
        RECT 47.570 0.070 47.650 0.560 ;
        RECT 48.490 0.070 48.570 0.560 ;
        RECT 49.410 0.070 49.490 0.560 ;
        RECT 50.330 0.070 50.410 0.560 ;
        RECT 51.250 0.070 51.330 0.560 ;
        RECT 52.170 0.070 52.250 0.560 ;
        RECT 53.090 0.070 53.170 0.560 ;
        RECT 54.010 0.070 54.090 0.560 ;
        RECT 54.930 0.070 57.770 0.560 ;
        RECT 58.610 0.070 58.690 0.560 ;
        RECT 59.530 0.070 60.530 0.560 ;
        RECT 61.370 0.070 61.450 0.560 ;
        RECT 62.290 0.070 62.370 0.560 ;
        RECT 63.210 0.070 63.290 0.560 ;
        RECT 64.130 0.070 67.890 0.560 ;
        RECT 68.730 0.070 73.410 0.560 ;
        RECT 74.250 0.070 74.330 0.560 ;
        RECT 75.170 0.070 75.250 0.560 ;
        RECT 76.090 0.070 76.170 0.560 ;
        RECT 77.010 0.070 77.090 0.560 ;
        RECT 77.930 0.070 81.690 0.560 ;
        RECT 82.530 0.070 86.290 0.560 ;
        RECT 87.130 0.070 88.130 0.560 ;
        RECT 88.970 0.070 89.050 0.560 ;
        RECT 89.890 0.070 89.970 0.560 ;
        RECT 90.810 0.070 90.890 0.560 ;
        RECT 91.730 0.070 91.810 0.560 ;
        RECT 92.650 0.070 101.010 0.560 ;
        RECT 101.850 0.070 102.850 0.560 ;
        RECT 103.690 0.070 103.770 0.560 ;
        RECT 104.610 0.070 106.530 0.560 ;
        RECT 107.370 0.070 108.370 0.560 ;
        RECT 109.210 0.070 113.890 0.560 ;
        RECT 114.730 0.070 117.570 0.560 ;
        RECT 118.410 0.070 136.070 0.560 ;
      LAYER met3 ;
        RECT 0.600 130.240 137.915 136.165 ;
        RECT 1.000 128.880 137.915 130.240 ;
        RECT 1.000 128.840 137.515 128.880 ;
        RECT 0.600 124.760 137.515 128.840 ;
        RECT 0.600 109.840 137.915 124.760 ;
        RECT 1.000 107.080 137.915 109.840 ;
        RECT 0.600 101.680 137.915 107.080 ;
        RECT 1.000 98.960 137.915 101.680 ;
        RECT 1.000 98.920 137.515 98.960 ;
        RECT 0.600 97.600 137.515 98.920 ;
        RECT 1.000 96.200 137.515 97.600 ;
        RECT 0.600 94.880 137.515 96.200 ;
        RECT 1.000 93.480 137.515 94.880 ;
        RECT 0.600 88.080 137.915 93.480 ;
        RECT 1.000 86.720 137.915 88.080 ;
        RECT 1.000 83.960 137.515 86.720 ;
        RECT 0.600 75.840 137.515 83.960 ;
        RECT 1.000 71.720 137.515 75.840 ;
        RECT 0.600 69.040 137.515 71.720 ;
        RECT 1.000 67.640 137.515 69.040 ;
        RECT 0.600 63.600 137.515 67.640 ;
        RECT 1.000 62.200 137.515 63.600 ;
        RECT 0.600 60.880 137.515 62.200 ;
        RECT 1.000 59.480 137.515 60.880 ;
        RECT 0.600 54.080 137.515 59.480 ;
        RECT 1.000 51.320 137.515 54.080 ;
        RECT 0.600 50.000 137.515 51.320 ;
        RECT 1.000 49.960 137.515 50.000 ;
        RECT 1.000 48.640 137.915 49.960 ;
        RECT 1.000 44.520 137.515 48.640 ;
        RECT 0.600 41.800 137.515 44.520 ;
        RECT 0.600 40.480 137.915 41.800 ;
        RECT 0.600 39.080 137.515 40.480 ;
        RECT 0.600 36.400 137.915 39.080 ;
        RECT 1.000 35.000 137.515 36.400 ;
        RECT 0.600 33.680 137.515 35.000 ;
        RECT 1.000 32.280 137.515 33.680 ;
        RECT 0.600 29.600 137.915 32.280 ;
        RECT 0.600 28.240 137.515 29.600 ;
        RECT 1.000 26.840 137.515 28.240 ;
        RECT 0.600 20.080 137.915 26.840 ;
        RECT 0.600 15.960 137.515 20.080 ;
        RECT 0.600 10.715 137.915 15.960 ;
      LAYER met4 ;
        RECT 23.295 13.095 23.940 125.625 ;
        RECT 26.340 13.095 120.225 125.625 ;
  END
END pmu
END LIBRARY

